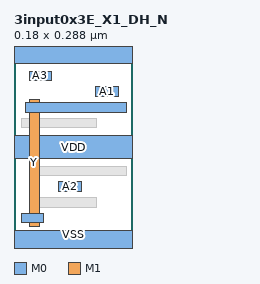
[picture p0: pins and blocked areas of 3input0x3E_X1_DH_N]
MACRO 3input0x3E_X1_DH_N
  CLASS CORE ;
  ORIGIN 0 0 ;
  FOREIGN 3input0x3E_X1_DH_N 0 0 ;
  SIZE 0.1800 BY 0.2880 ;
  SYMMETRY X Y ;
  SITE coresite ;
  PIN A1
    DIRECTION INPUT ;
    USE SIGNAL ;
    PORT
      LAYER M0 ;
        RECT 0.1230 0.2210 0.1580 0.2350 ;
    END
  END A1
  PIN A2
    DIRECTION INPUT ;
    USE SIGNAL ;
    PORT
      LAYER M0 ;
        RECT 0.0680 0.0770 0.1020 0.0910 ;
    END
  END A2
  PIN A3
    DIRECTION INPUT ;
    USE SIGNAL ;
    PORT
      LAYER M0 ;
        RECT 0.0230 0.2450 0.0570 0.2590 ;
    END
  END A3
  PIN Y
    DIRECTION OUTPUT ;
    USE SIGNAL ;
    PORT
      LAYER M1 ;
        RECT 0.0230 0.0240 0.0380 0.2160 ;
      LAYER M0 ;
        RECT 0.0110 0.0290 0.0450 0.0430 ;
        RECT 0.0180 0.1970 0.1700 0.2110 ;
    END
  END Y
  PIN VDD
    DIRECTION INOUT ;
    USE POWER ;
    SHAPE ABUTMENT ;
    PORT
      LAYER M0 ;
        RECT 0.0000 0.1260 0.1800 0.1620 ;
    END
  END VDD
  PIN VSS
    DIRECTION INOUT ;
    USE GROUND ;
    SHAPE ABUTMENT ;
    PORT
      LAYER M0 ;
        RECT 0.0000 -0.0180 0.1800 0.0180 ;
        RECT 0.0000 0.2700 0.1800 0.3060 ;
    END
  END VSS
  OBS
    LAYER V0 ;
      RECT 0.0230 0.0290 0.0370 0.0430 ;
      RECT 0.0230 0.1970 0.0370 0.2110 ;
    LAYER M0 ;
      RECT 0.0330 0.0530 0.1250 0.0670 ;
      RECT 0.0330 0.1010 0.1700 0.1150 ;
      RECT 0.0110 0.1730 0.1250 0.1870 ;
  END
END 3input0x3E_X1_DH_N
